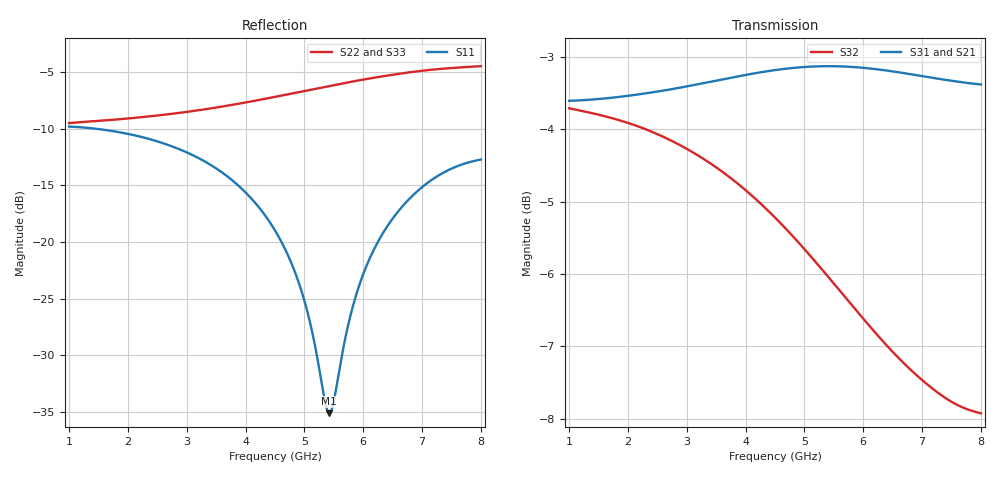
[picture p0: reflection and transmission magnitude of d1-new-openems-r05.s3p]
! Order 0 openEMS 3D prediction: d1-r05 (43 um copper, nominal FR408HR)
! renormalized from each port's line impedance to 50 ohm; e^(+jwt)
# HZ S RI R 50
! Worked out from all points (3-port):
!   701 points, 1 GHz to 8 GHz, reference 50 ohm
!   strongest paths, dB at 1 GHz, 2.75 GHz, 4.5 GHz, 6.25 GHz, 8 GHz:
!     S31: -3.6, -3.4, -3.2, -3.2, -3.4
!     S21: -3.6, -3.4, -3.2, -3.2, -3.4
!     S32: -3.7, -4.2, -5.2, -6.9, -7.9
!   lowest |S11| = -35.1 dB at 5.42 GHz (marker M1), VSWR 1.04, Z = 51.8 - j0.00534 ohm
!   |S11| at or under -10 dB: 1.431 GHz to end of sweep
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1e9  -0.3144 0.0722  0.5907 -0.2956  0.5909 -0.2959
     0.5888 -0.2978  -0.2938 0.1596  0.5406 -0.3652
     0.5891 -0.2982  0.5406 -0.3652  -0.2932 0.1594
1.87e9  -0.2739 0.1323  0.4266 -0.5098  0.4266 -0.5098
        0.4266 -0.5095  -0.1995 0.2851  0.2819 -0.5744
        0.4266 -0.5095  0.2819 -0.5744  -0.1995 0.2851
2.66e9  -0.2095 0.1688  0.2139 -0.6367  0.2142 -0.6366
        0.2138 -0.6367  -0.0531 0.3612  -0.00938 -0.6218
        0.214 -0.6366  -0.00938 -0.6218  -0.0534 0.3612
4.5e9  -0.0195 0.1107  -0.3737 -0.5841  -0.3738 -0.5846
       -0.3738 -0.5834  0.377 0.2198  -0.4859 -0.254
       -0.3738 -0.5839  -0.4859 -0.254  0.3763 0.2198
4.98e9  0.00957 0.0565  -0.5041 -0.4809  -0.5044 -0.4813
        -0.504 -0.4802  0.4515 0.0994  -0.5105 -0.1116
        -0.5043 -0.4806  -0.5105 -0.1116  0.4507 0.0994
5.42e9  0.0175 -5.15e-05  -0.598 -0.3592  -0.5984 -0.3594
        -0.5979 -0.3587  0.4864 -0.0301  -0.498 0.0101
        -0.5982 -0.3589  -0.498 0.0101  0.4858 -0.0301
5.87e9  0.00498 -0.057  -0.6623 -0.2155  -0.6626 -0.2155
        -0.6622 -0.2151  0.4841 -0.1699  -0.4588 0.1177
        -0.6625 -0.2151  -0.4588 0.1177  0.4837 -0.1699
6.33e9  -0.028 -0.1051  -0.691 -0.0583  -0.6912 -0.0582
        -0.6907 -0.0582  0.4415 -0.3071  -0.4005 0.2064
        -0.691 -0.058  -0.4005 0.2064  0.4412 -0.3072
7.08e9  -0.11 -0.1439  -0.6573 0.1949  -0.6575 0.1955
        -0.6574 0.1943  0.2976 -0.4886  -0.287 0.3077
        -0.6576 0.1949  -0.287 0.3077  0.2967 -0.4887
8e9  -0.2045 -0.1071  -0.5025 0.4554  -0.5024 0.4555
     -0.5029 0.4541  0.0576 -0.5934  -0.139 0.3767
     -0.5028 0.4542  -0.139 0.3767  0.0574 -0.5933
